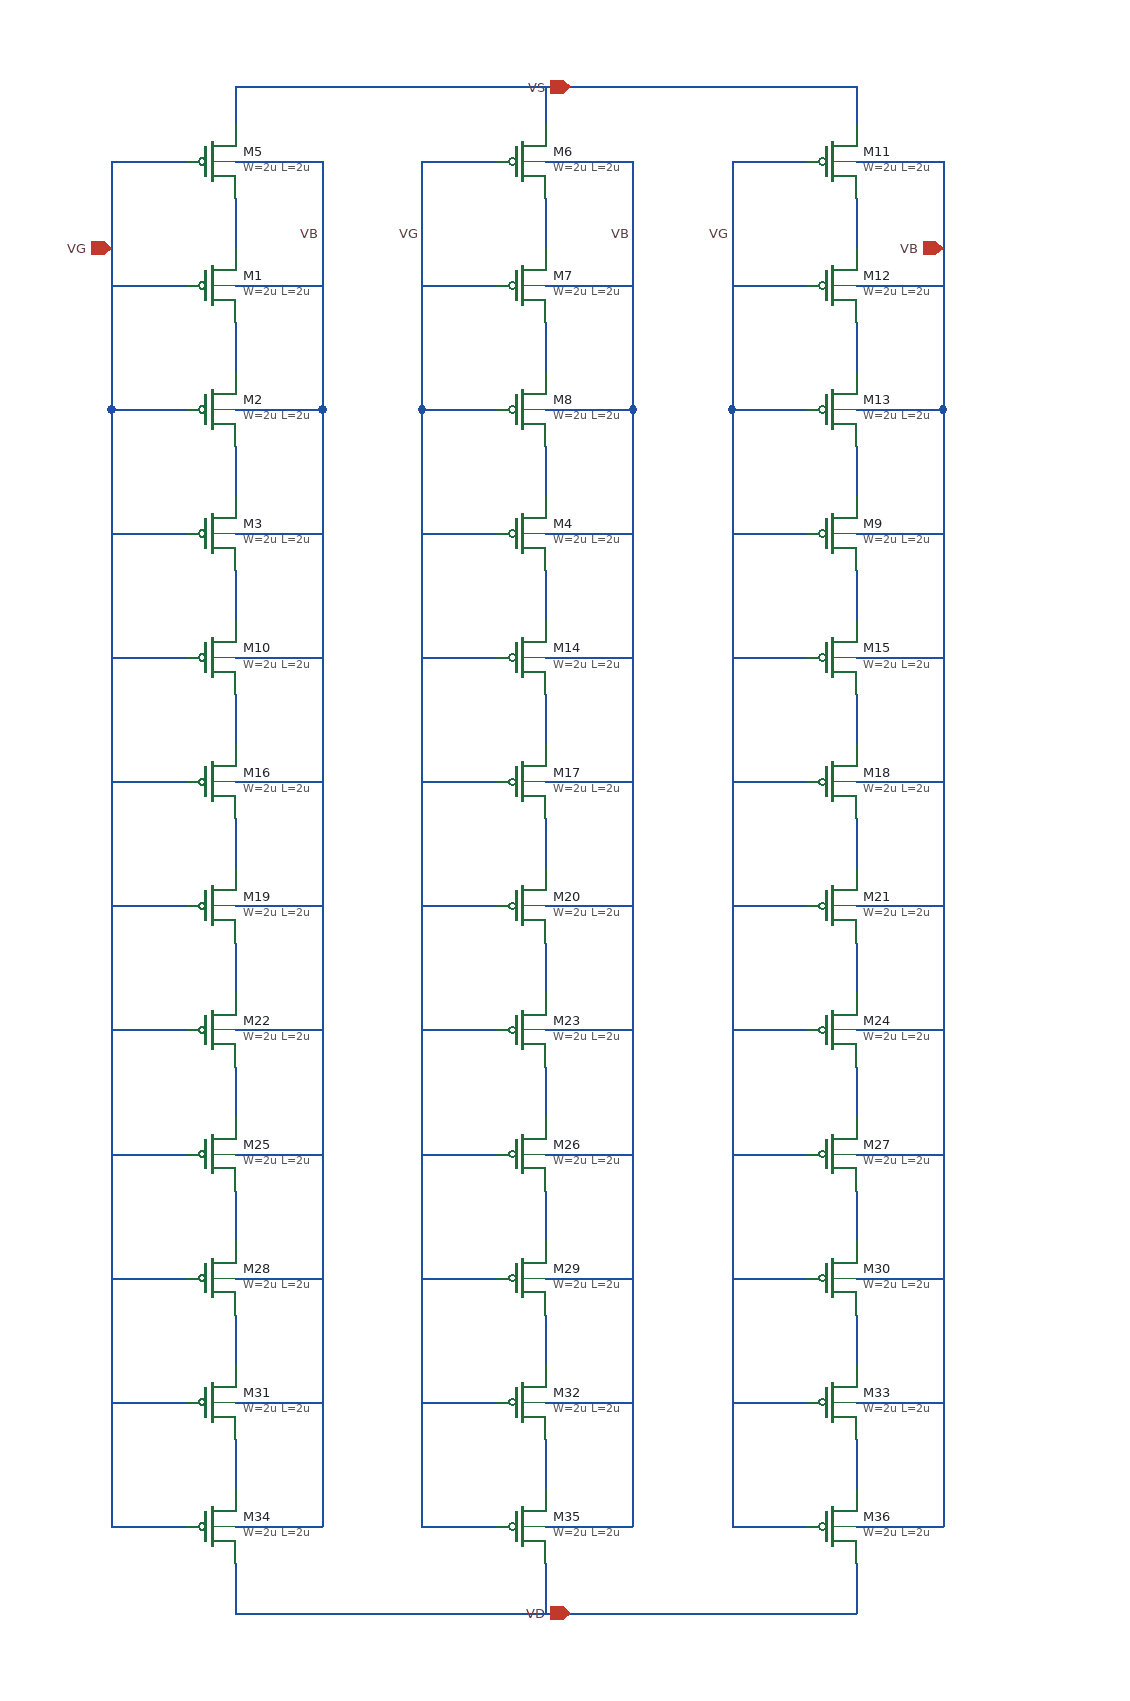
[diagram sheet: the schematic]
v {xschem version=3.4.5 file_version=1.2
}
G {}
K {}
V {}
S {}
E {}
N -250 -110 -250 -80 {
lab=VS}
N -250 -20 -250 20 {
lab=#net1}
N -250 -50 -180 -50 {
lab=VB}
N -350 -50 -290 -50 {
lab=VG}
N -250 80 -250 120 {
lab=#net2}
N -250 1080 -250 1120 {
lab=VD}
N -350 150 -290 150 {
lab=VG}
N -350 50 -290 50 {
lab=VG}
N -250 150 -180 150 {
lab=VB}
N -250 50 -180 50 {
lab=VB}
N 0 -110 0 -80 {
lab=VS}
N 0 -20 0 20 {
lab=#net3}
N 0 -50 70 -50 {
lab=VB}
N -100 -50 -40 -50 {
lab=VG}
N 0 80 0 120 {
lab=#net4}
N 0 1080 0 1120 {
lab=VD}
N -100 150 -40 150 {
lab=VG}
N -100 50 -40 50 {
lab=VG}
N 0 150 70 150 {
lab=VB}
N 0 50 70 50 {
lab=VB}
N 250 -110 250 -80 {
lab=VS}
N 250 -20 250 20 {
lab=#net5}
N 250 -50 320 -50 {
lab=VB}
N 150 -50 210 -50 {
lab=#net6}
N 250 80 250 120 {
lab=#net7}
N 250 1080 250 1120 {
lab=VD}
N 150 150 210 150 {
lab=#net6}
N 150 50 210 50 {
lab=#net6}
N 250 150 320 150 {
lab=VB}
N 250 50 320 50 {
lab=VB}
N -250 -110 250 -110 {
lab=VS}
N -250 1120 250 1120 {
lab=VD}
N -350 -50 -350 150 {
lab=VG}
N -180 -50 -180 150 {
lab=VB}
N -100 -50 -100 140 {
lab=VG}
N -100 140 -100 150 {
lab=VG}
N 70 -50 70 150 {
lab=VB}
N 150 -50 150 150 {
lab=#net6}
N 320 -50 320 150 {
lab=VB}
N -250 180 -250 220 {
lab=#net2}
N -250 250 -180 250 {
lab=VB}
N 0 180 0 220 {
lab=#net4}
N -100 250 -40 250 {
lab=VG}
N 0 250 70 250 {
lab=VB}
N 250 180 250 220 {
lab=#net7}
N 150 250 210 250 {
lab=#net6}
N -250 280 -250 320 {
lab=#net2}
N -250 350 -180 350 {
lab=VB}
N 0 280 0 320 {
lab=#net4}
N -100 350 -40 350 {
lab=VG}
N 0 350 70 350 {
lab=VB}
N 250 280 250 320 {
lab=#net7}
N 150 350 210 350 {
lab=#net6}
N -250 380 -250 420 {
lab=#net2}
N -250 450 -180 450 {
lab=VB}
N 0 380 0 420 {
lab=#net4}
N -100 450 -40 450 {
lab=VG}
N 0 450 70 450 {
lab=VB}
N 250 380 250 420 {
lab=#net7}
N 150 450 210 450 {
lab=#net6}
N -250 480 -250 520 {
lab=#net2}
N -250 550 -180 550 {
lab=VB}
N 0 480 0 520 {
lab=#net4}
N -100 550 -40 550 {
lab=VG}
N 0 550 70 550 {
lab=VB}
N 250 480 250 520 {
lab=#net7}
N 150 550 210 550 {
lab=#net6}
N -250 580 -250 620 {
lab=#net2}
N -250 650 -180 650 {
lab=VB}
N 0 580 0 620 {
lab=#net4}
N -100 650 -40 650 {
lab=VG}
N 0 650 70 650 {
lab=VB}
N 250 580 250 620 {
lab=#net7}
N 150 650 210 650 {
lab=#net6}
N -250 680 -250 720 {
lab=#net2}
N -250 750 -180 750 {
lab=VB}
N 0 680 0 720 {
lab=#net4}
N -100 750 -40 750 {
lab=VG}
N 0 750 70 750 {
lab=VB}
N 250 680 250 720 {
lab=#net7}
N 150 750 210 750 {
lab=#net6}
N -250 780 -250 820 {
lab=#net2}
N -250 850 -180 850 {
lab=VB}
N 0 780 0 820 {
lab=#net4}
N -100 850 -40 850 {
lab=VG}
N 0 850 70 850 {
lab=VB}
N 250 780 250 820 {
lab=#net7}
N 150 850 210 850 {
lab=#net6}
N -250 880 -250 920 {
lab=#net2}
N -250 950 -180 950 {
lab=VB}
N 0 880 0 920 {
lab=#net4}
N -100 950 -40 950 {
lab=VG}
N 0 950 70 950 {
lab=VB}
N 250 880 250 920 {
lab=#net7}
N 150 950 210 950 {
lab=#net6}
N -250 980 -250 1020 {
lab=#net2}
N -250 1050 -180 1050 {
lab=VB}
N 0 980 0 1020 {
lab=#net4}
N -100 1050 -40 1050 {
lab=VG}
N 0 1050 70 1050 {
lab=VB}
N 250 980 250 1020 {
lab=#net7}
N 150 1050 210 1050 {
lab=#net6}
N -100 1040 -100 1050 {
lab=VG}
N -100 150 -100 1040 {}
N 70 150 70 1050 {}
N 150 150 150 1050 {}
N 320 150 320 1050 {}
N 250 1050 320 1050 {}
N 250 950 320 950 {}
N 250 850 320 850 {}
N 250 750 320 750 {}
N 250 650 310 650 {}
N 310 650 320 650 {}
N 250 550 320 550 {}
N 250 450 320 450 {}
N 250 350 320 350 {}
N 250 250 320 250 {}
N -180 150 -180 1050 {}
N -350 150 -350 1050 {}
N -350 1050 -290 1050 {}
N -350 950 -290 950 {}
N -350 850 -290 850 {}
N -350 750 -290 750 {}
N -350 650 -290 650 {}
N -350 550 -290 550 {}
N -350 450 -290 450 {}
N -350 350 -290 350 {}
N -350 250 -290 250 {}
C {devices/iopin.sym} 320 20 0 0 {name=p2 lab=VB}
C {devices/iopin.sym} -350 20 2 0 {name=p3 lab=VG}
C {symbols/pfet_03v3.sym} -270 -50 0 0 {name=M5
L=2u
W=2u
nf=1
m=1
ad="'int((nf+1)/2) * W/nf * 0.18u'"
pd="'2*int((nf+1)/2) * (W/nf + 0.18u)'"
as="'int((nf+2)/2) * W/nf * 0.18u'"
ps="'2*int((nf+2)/2) * (W/nf + 0.18u)'"
nrd="'0.18u / W'" nrs="'0.18u / W'"
sa=0 sb=0 sd=0
model=pfet_03v3
spiceprefix=X
}
C {devices/iopin.sym} 20 -110 3 0 {name=p4 lab=VS}
C {devices/iopin.sym} 20 1120 1 0 {name=p1 lab=VD}
C {symbols/pfet_03v3.sym} -270 50 0 0 {name=M1
L=2u
W=2u
nf=1
m=1
ad="'int((nf+1)/2) * W/nf * 0.18u'"
pd="'2*int((nf+1)/2) * (W/nf + 0.18u)'"
as="'int((nf+2)/2) * W/nf * 0.18u'"
ps="'2*int((nf+2)/2) * (W/nf + 0.18u)'"
nrd="'0.18u / W'" nrs="'0.18u / W'"
sa=0 sb=0 sd=0
model=pfet_03v3
spiceprefix=X
}
C {symbols/pfet_03v3.sym} -270 150 0 0 {name=M2
L=2u
W=2u
nf=1
m=1
ad="'int((nf+1)/2) * W/nf * 0.18u'"
pd="'2*int((nf+1)/2) * (W/nf + 0.18u)'"
as="'int((nf+2)/2) * W/nf * 0.18u'"
ps="'2*int((nf+2)/2) * (W/nf + 0.18u)'"
nrd="'0.18u / W'" nrs="'0.18u / W'"
sa=0 sb=0 sd=0
model=pfet_03v3
spiceprefix=X
}
C {symbols/pfet_03v3.sym} -20 -50 0 0 {name=M6
L=2u
W=2u
nf=1
m=1
ad="'int((nf+1)/2) * W/nf * 0.18u'"
pd="'2*int((nf+1)/2) * (W/nf + 0.18u)'"
as="'int((nf+2)/2) * W/nf * 0.18u'"
ps="'2*int((nf+2)/2) * (W/nf + 0.18u)'"
nrd="'0.18u / W'" nrs="'0.18u / W'"
sa=0 sb=0 sd=0
model=pfet_03v3
spiceprefix=X
}
C {symbols/pfet_03v3.sym} -20 50 0 0 {name=M7
L=2u
W=2u
nf=1
m=1
ad="'int((nf+1)/2) * W/nf * 0.18u'"
pd="'2*int((nf+1)/2) * (W/nf + 0.18u)'"
as="'int((nf+2)/2) * W/nf * 0.18u'"
ps="'2*int((nf+2)/2) * (W/nf + 0.18u)'"
nrd="'0.18u / W'" nrs="'0.18u / W'"
sa=0 sb=0 sd=0
model=pfet_03v3
spiceprefix=X
}
C {symbols/pfet_03v3.sym} -20 150 0 0 {name=M8
L=2u
W=2u
nf=1
m=1
ad="'int((nf+1)/2) * W/nf * 0.18u'"
pd="'2*int((nf+1)/2) * (W/nf + 0.18u)'"
as="'int((nf+2)/2) * W/nf * 0.18u'"
ps="'2*int((nf+2)/2) * (W/nf + 0.18u)'"
nrd="'0.18u / W'" nrs="'0.18u / W'"
sa=0 sb=0 sd=0
model=pfet_03v3
spiceprefix=X
}
C {symbols/pfet_03v3.sym} 230 -50 0 0 {name=M11
L=2u
W=2u
nf=1
m=1
ad="'int((nf+1)/2) * W/nf * 0.18u'"
pd="'2*int((nf+1)/2) * (W/nf + 0.18u)'"
as="'int((nf+2)/2) * W/nf * 0.18u'"
ps="'2*int((nf+2)/2) * (W/nf + 0.18u)'"
nrd="'0.18u / W'" nrs="'0.18u / W'"
sa=0 sb=0 sd=0
model=pfet_03v3
spiceprefix=X
}
C {symbols/pfet_03v3.sym} 230 50 0 0 {name=M12
L=2u
W=2u
nf=1
m=1
ad="'int((nf+1)/2) * W/nf * 0.18u'"
pd="'2*int((nf+1)/2) * (W/nf + 0.18u)'"
as="'int((nf+2)/2) * W/nf * 0.18u'"
ps="'2*int((nf+2)/2) * (W/nf + 0.18u)'"
nrd="'0.18u / W'" nrs="'0.18u / W'"
sa=0 sb=0 sd=0
model=pfet_03v3
spiceprefix=X
}
C {symbols/pfet_03v3.sym} 230 150 0 0 {name=M13
L=2u
W=2u
nf=1
m=1
ad="'int((nf+1)/2) * W/nf * 0.18u'"
pd="'2*int((nf+1)/2) * (W/nf + 0.18u)'"
as="'int((nf+2)/2) * W/nf * 0.18u'"
ps="'2*int((nf+2)/2) * (W/nf + 0.18u)'"
nrd="'0.18u / W'" nrs="'0.18u / W'"
sa=0 sb=0 sd=0
model=pfet_03v3
spiceprefix=X
}
C {devices/lab_wire.sym} -180 10 0 0 {name=p9 sig_type=std_logic lab=VB}
C {devices/lab_wire.sym} 70 10 0 0 {name=p5 sig_type=std_logic lab=VB}
C {devices/lab_wire.sym} -100 10 0 0 {name=p6 sig_type=std_logic lab=VG
}
C {devices/lab_wire.sym} 150 10 0 0 {name=p7 sig_type=std_logic lab=VG
}
C {symbols/pfet_03v3.sym} -270 250 0 0 {name=M3
L=2u
W=2u
nf=1
m=1
ad="'int((nf+1)/2) * W/nf * 0.18u'"
pd="'2*int((nf+1)/2) * (W/nf + 0.18u)'"
as="'int((nf+2)/2) * W/nf * 0.18u'"
ps="'2*int((nf+2)/2) * (W/nf + 0.18u)'"
nrd="'0.18u / W'" nrs="'0.18u / W'"
sa=0 sb=0 sd=0
model=pfet_03v3
spiceprefix=X
}
C {symbols/pfet_03v3.sym} -20 250 0 0 {name=M4
L=2u
W=2u
nf=1
m=1
ad="'int((nf+1)/2) * W/nf * 0.18u'"
pd="'2*int((nf+1)/2) * (W/nf + 0.18u)'"
as="'int((nf+2)/2) * W/nf * 0.18u'"
ps="'2*int((nf+2)/2) * (W/nf + 0.18u)'"
nrd="'0.18u / W'" nrs="'0.18u / W'"
sa=0 sb=0 sd=0
model=pfet_03v3
spiceprefix=X
}
C {symbols/pfet_03v3.sym} 230 250 0 0 {name=M9
L=2u
W=2u
nf=1
m=1
ad="'int((nf+1)/2) * W/nf * 0.18u'"
pd="'2*int((nf+1)/2) * (W/nf + 0.18u)'"
as="'int((nf+2)/2) * W/nf * 0.18u'"
ps="'2*int((nf+2)/2) * (W/nf + 0.18u)'"
nrd="'0.18u / W'" nrs="'0.18u / W'"
sa=0 sb=0 sd=0
model=pfet_03v3
spiceprefix=X
}
C {symbols/pfet_03v3.sym} -270 350 0 0 {name=M10
L=2u
W=2u
nf=1
m=1
ad="'int((nf+1)/2) * W/nf * 0.18u'"
pd="'2*int((nf+1)/2) * (W/nf + 0.18u)'"
as="'int((nf+2)/2) * W/nf * 0.18u'"
ps="'2*int((nf+2)/2) * (W/nf + 0.18u)'"
nrd="'0.18u / W'" nrs="'0.18u / W'"
sa=0 sb=0 sd=0
model=pfet_03v3
spiceprefix=X
}
C {symbols/pfet_03v3.sym} -20 350 0 0 {name=M14
L=2u
W=2u
nf=1
m=1
ad="'int((nf+1)/2) * W/nf * 0.18u'"
pd="'2*int((nf+1)/2) * (W/nf + 0.18u)'"
as="'int((nf+2)/2) * W/nf * 0.18u'"
ps="'2*int((nf+2)/2) * (W/nf + 0.18u)'"
nrd="'0.18u / W'" nrs="'0.18u / W'"
sa=0 sb=0 sd=0
model=pfet_03v3
spiceprefix=X
}
C {symbols/pfet_03v3.sym} 230 350 0 0 {name=M15
L=2u
W=2u
nf=1
m=1
ad="'int((nf+1)/2) * W/nf * 0.18u'"
pd="'2*int((nf+1)/2) * (W/nf + 0.18u)'"
as="'int((nf+2)/2) * W/nf * 0.18u'"
ps="'2*int((nf+2)/2) * (W/nf + 0.18u)'"
nrd="'0.18u / W'" nrs="'0.18u / W'"
sa=0 sb=0 sd=0
model=pfet_03v3
spiceprefix=X
}
C {symbols/pfet_03v3.sym} -270 450 0 0 {name=M16
L=2u
W=2u
nf=1
m=1
ad="'int((nf+1)/2) * W/nf * 0.18u'"
pd="'2*int((nf+1)/2) * (W/nf + 0.18u)'"
as="'int((nf+2)/2) * W/nf * 0.18u'"
ps="'2*int((nf+2)/2) * (W/nf + 0.18u)'"
nrd="'0.18u / W'" nrs="'0.18u / W'"
sa=0 sb=0 sd=0
model=pfet_03v3
spiceprefix=X
}
C {symbols/pfet_03v3.sym} -20 450 0 0 {name=M17
L=2u
W=2u
nf=1
m=1
ad="'int((nf+1)/2) * W/nf * 0.18u'"
pd="'2*int((nf+1)/2) * (W/nf + 0.18u)'"
as="'int((nf+2)/2) * W/nf * 0.18u'"
ps="'2*int((nf+2)/2) * (W/nf + 0.18u)'"
nrd="'0.18u / W'" nrs="'0.18u / W'"
sa=0 sb=0 sd=0
model=pfet_03v3
spiceprefix=X
}
C {symbols/pfet_03v3.sym} 230 450 0 0 {name=M18
L=2u
W=2u
nf=1
m=1
ad="'int((nf+1)/2) * W/nf * 0.18u'"
pd="'2*int((nf+1)/2) * (W/nf + 0.18u)'"
as="'int((nf+2)/2) * W/nf * 0.18u'"
ps="'2*int((nf+2)/2) * (W/nf + 0.18u)'"
nrd="'0.18u / W'" nrs="'0.18u / W'"
sa=0 sb=0 sd=0
model=pfet_03v3
spiceprefix=X
}
C {symbols/pfet_03v3.sym} -270 550 0 0 {name=M19
L=2u
W=2u
nf=1
m=1
ad="'int((nf+1)/2) * W/nf * 0.18u'"
pd="'2*int((nf+1)/2) * (W/nf + 0.18u)'"
as="'int((nf+2)/2) * W/nf * 0.18u'"
ps="'2*int((nf+2)/2) * (W/nf + 0.18u)'"
nrd="'0.18u / W'" nrs="'0.18u / W'"
sa=0 sb=0 sd=0
model=pfet_03v3
spiceprefix=X
}
C {symbols/pfet_03v3.sym} -20 550 0 0 {name=M20
L=2u
W=2u
nf=1
m=1
ad="'int((nf+1)/2) * W/nf * 0.18u'"
pd="'2*int((nf+1)/2) * (W/nf + 0.18u)'"
as="'int((nf+2)/2) * W/nf * 0.18u'"
ps="'2*int((nf+2)/2) * (W/nf + 0.18u)'"
nrd="'0.18u / W'" nrs="'0.18u / W'"
sa=0 sb=0 sd=0
model=pfet_03v3
spiceprefix=X
}
C {symbols/pfet_03v3.sym} 230 550 0 0 {name=M21
L=2u
W=2u
nf=1
m=1
ad="'int((nf+1)/2) * W/nf * 0.18u'"
pd="'2*int((nf+1)/2) * (W/nf + 0.18u)'"
as="'int((nf+2)/2) * W/nf * 0.18u'"
ps="'2*int((nf+2)/2) * (W/nf + 0.18u)'"
nrd="'0.18u / W'" nrs="'0.18u / W'"
sa=0 sb=0 sd=0
model=pfet_03v3
spiceprefix=X
}
C {symbols/pfet_03v3.sym} -270 650 0 0 {name=M22
L=2u
W=2u
nf=1
m=1
ad="'int((nf+1)/2) * W/nf * 0.18u'"
pd="'2*int((nf+1)/2) * (W/nf + 0.18u)'"
as="'int((nf+2)/2) * W/nf * 0.18u'"
ps="'2*int((nf+2)/2) * (W/nf + 0.18u)'"
nrd="'0.18u / W'" nrs="'0.18u / W'"
sa=0 sb=0 sd=0
model=pfet_03v3
spiceprefix=X
}
C {symbols/pfet_03v3.sym} -20 650 0 0 {name=M23
L=2u
W=2u
nf=1
m=1
ad="'int((nf+1)/2) * W/nf * 0.18u'"
pd="'2*int((nf+1)/2) * (W/nf + 0.18u)'"
as="'int((nf+2)/2) * W/nf * 0.18u'"
ps="'2*int((nf+2)/2) * (W/nf + 0.18u)'"
nrd="'0.18u / W'" nrs="'0.18u / W'"
sa=0 sb=0 sd=0
model=pfet_03v3
spiceprefix=X
}
C {symbols/pfet_03v3.sym} 230 650 0 0 {name=M24
L=2u
W=2u
nf=1
m=1
ad="'int((nf+1)/2) * W/nf * 0.18u'"
pd="'2*int((nf+1)/2) * (W/nf + 0.18u)'"
as="'int((nf+2)/2) * W/nf * 0.18u'"
ps="'2*int((nf+2)/2) * (W/nf + 0.18u)'"
nrd="'0.18u / W'" nrs="'0.18u / W'"
sa=0 sb=0 sd=0
model=pfet_03v3
spiceprefix=X
}
C {symbols/pfet_03v3.sym} -270 750 0 0 {name=M25
L=2u
W=2u
nf=1
m=1
ad="'int((nf+1)/2) * W/nf * 0.18u'"
pd="'2*int((nf+1)/2) * (W/nf + 0.18u)'"
as="'int((nf+2)/2) * W/nf * 0.18u'"
ps="'2*int((nf+2)/2) * (W/nf + 0.18u)'"
nrd="'0.18u / W'" nrs="'0.18u / W'"
sa=0 sb=0 sd=0
model=pfet_03v3
spiceprefix=X
}
C {symbols/pfet_03v3.sym} -20 750 0 0 {name=M26
L=2u
W=2u
nf=1
m=1
ad="'int((nf+1)/2) * W/nf * 0.18u'"
pd="'2*int((nf+1)/2) * (W/nf + 0.18u)'"
as="'int((nf+2)/2) * W/nf * 0.18u'"
ps="'2*int((nf+2)/2) * (W/nf + 0.18u)'"
nrd="'0.18u / W'" nrs="'0.18u / W'"
sa=0 sb=0 sd=0
model=pfet_03v3
spiceprefix=X
}
C {symbols/pfet_03v3.sym} 230 750 0 0 {name=M27
L=2u
W=2u
nf=1
m=1
ad="'int((nf+1)/2) * W/nf * 0.18u'"
pd="'2*int((nf+1)/2) * (W/nf + 0.18u)'"
as="'int((nf+2)/2) * W/nf * 0.18u'"
ps="'2*int((nf+2)/2) * (W/nf + 0.18u)'"
nrd="'0.18u / W'" nrs="'0.18u / W'"
sa=0 sb=0 sd=0
model=pfet_03v3
spiceprefix=X
}
C {symbols/pfet_03v3.sym} -270 850 0 0 {name=M28
L=2u
W=2u
nf=1
m=1
ad="'int((nf+1)/2) * W/nf * 0.18u'"
pd="'2*int((nf+1)/2) * (W/nf + 0.18u)'"
as="'int((nf+2)/2) * W/nf * 0.18u'"
ps="'2*int((nf+2)/2) * (W/nf + 0.18u)'"
nrd="'0.18u / W'" nrs="'0.18u / W'"
sa=0 sb=0 sd=0
model=pfet_03v3
spiceprefix=X
}
C {symbols/pfet_03v3.sym} -20 850 0 0 {name=M29
L=2u
W=2u
nf=1
m=1
ad="'int((nf+1)/2) * W/nf * 0.18u'"
pd="'2*int((nf+1)/2) * (W/nf + 0.18u)'"
as="'int((nf+2)/2) * W/nf * 0.18u'"
ps="'2*int((nf+2)/2) * (W/nf + 0.18u)'"
nrd="'0.18u / W'" nrs="'0.18u / W'"
sa=0 sb=0 sd=0
model=pfet_03v3
spiceprefix=X
}
C {symbols/pfet_03v3.sym} 230 850 0 0 {name=M30
L=2u
W=2u
nf=1
m=1
ad="'int((nf+1)/2) * W/nf * 0.18u'"
pd="'2*int((nf+1)/2) * (W/nf + 0.18u)'"
as="'int((nf+2)/2) * W/nf * 0.18u'"
ps="'2*int((nf+2)/2) * (W/nf + 0.18u)'"
nrd="'0.18u / W'" nrs="'0.18u / W'"
sa=0 sb=0 sd=0
model=pfet_03v3
spiceprefix=X
}
C {symbols/pfet_03v3.sym} -270 950 0 0 {name=M31
L=2u
W=2u
nf=1
m=1
ad="'int((nf+1)/2) * W/nf * 0.18u'"
pd="'2*int((nf+1)/2) * (W/nf + 0.18u)'"
as="'int((nf+2)/2) * W/nf * 0.18u'"
ps="'2*int((nf+2)/2) * (W/nf + 0.18u)'"
nrd="'0.18u / W'" nrs="'0.18u / W'"
sa=0 sb=0 sd=0
model=pfet_03v3
spiceprefix=X
}
C {symbols/pfet_03v3.sym} -20 950 0 0 {name=M32
L=2u
W=2u
nf=1
m=1
ad="'int((nf+1)/2) * W/nf * 0.18u'"
pd="'2*int((nf+1)/2) * (W/nf + 0.18u)'"
as="'int((nf+2)/2) * W/nf * 0.18u'"
ps="'2*int((nf+2)/2) * (W/nf + 0.18u)'"
nrd="'0.18u / W'" nrs="'0.18u / W'"
sa=0 sb=0 sd=0
model=pfet_03v3
spiceprefix=X
}
C {symbols/pfet_03v3.sym} 230 950 0 0 {name=M33
L=2u
W=2u
nf=1
m=1
ad="'int((nf+1)/2) * W/nf * 0.18u'"
pd="'2*int((nf+1)/2) * (W/nf + 0.18u)'"
as="'int((nf+2)/2) * W/nf * 0.18u'"
ps="'2*int((nf+2)/2) * (W/nf + 0.18u)'"
nrd="'0.18u / W'" nrs="'0.18u / W'"
sa=0 sb=0 sd=0
model=pfet_03v3
spiceprefix=X
}
C {symbols/pfet_03v3.sym} -270 1050 0 0 {name=M34
L=2u
W=2u
nf=1
m=1
ad="'int((nf+1)/2) * W/nf * 0.18u'"
pd="'2*int((nf+1)/2) * (W/nf + 0.18u)'"
as="'int((nf+2)/2) * W/nf * 0.18u'"
ps="'2*int((nf+2)/2) * (W/nf + 0.18u)'"
nrd="'0.18u / W'" nrs="'0.18u / W'"
sa=0 sb=0 sd=0
model=pfet_03v3
spiceprefix=X
}
C {symbols/pfet_03v3.sym} -20 1050 0 0 {name=M35
L=2u
W=2u
nf=1
m=1
ad="'int((nf+1)/2) * W/nf * 0.18u'"
pd="'2*int((nf+1)/2) * (W/nf + 0.18u)'"
as="'int((nf+2)/2) * W/nf * 0.18u'"
ps="'2*int((nf+2)/2) * (W/nf + 0.18u)'"
nrd="'0.18u / W'" nrs="'0.18u / W'"
sa=0 sb=0 sd=0
model=pfet_03v3
spiceprefix=X
}
C {symbols/pfet_03v3.sym} 230 1050 0 0 {name=M36
L=2u
W=2u
nf=1
m=1
ad="'int((nf+1)/2) * W/nf * 0.18u'"
pd="'2*int((nf+1)/2) * (W/nf + 0.18u)'"
as="'int((nf+2)/2) * W/nf * 0.18u'"
ps="'2*int((nf+2)/2) * (W/nf + 0.18u)'"
nrd="'0.18u / W'" nrs="'0.18u / W'"
sa=0 sb=0 sd=0
model=pfet_03v3
spiceprefix=X
}
